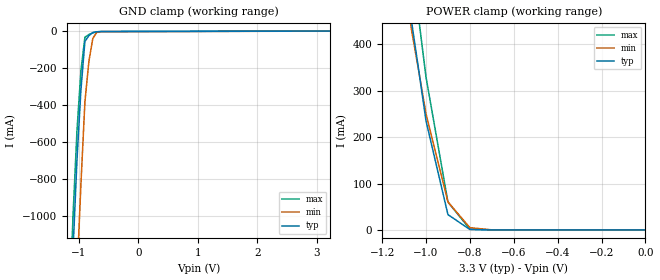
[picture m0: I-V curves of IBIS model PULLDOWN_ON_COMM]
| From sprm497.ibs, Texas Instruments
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|   Model Cell PULLDOWN_ON_COMM
[Model]   PULLDOWN_ON_COMM
Model_type   Input
Polarity   Non-Inverting
Vinl =  0.8
Vinh =  2
C_comp   0.8695239p   0.8563616p   0.8781626p
[Model Spec]
Vinl   0.8   0.8   0.8
Vinh   2   2   2
[Temperature Range]   25   105   0
[Voltage Range]   3.3   3.14   3.47
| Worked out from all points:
|   GND clamp passes 1 mA (typ) near -0.58 V on its own axis
|   POWER clamp passes 1 mA (typ) near -0.79 V on its own axis
[POWER_clamp]
|   voltage   I(typ)   I(min)   I(max)
-3.3V     9.572A     8.242A     10.54A
-1.067V   452.2mA    433.2mA    579.4mA
-1.033V   343.5mA    341.7mA    454.3mA
-1V       234.9mA    250.1mA    329.2mA
-900mV    33.1mA     60.41mA    60.11mA
-800mV    1.106mA    4.959mA    1.777mA
-700mV    117.1uA    319.8uA    148.3uA
-11.55fV  93.69uA    61.44uA    121.1uA
[GND_clamp]
|   voltage   I(typ)   I(min)   I(max)
-3.3V     -22.43A    -23.04A    -22.26A
-1.167V   -1.763A    -2.446A    -1.569A
-1.1V     -1.191A    -1.863A    -1.003A
-1.033V   -696.7mA   -1.322A    -538.1mA
-966.7mV  -318.5mA   -829.3mA   -215.1mA
-900mV    -56.2mA    -384.9mA   -33.57mA
-833.3mV  -25.19mA   -165.5mA   -18.58mA
-766.7mV  -7.722mA   -39.45mA   -8.986mA
-700mV    -3.804mA   -6.766mA   -4.783mA
-633.3mV  -1.959mA   -3.363mA   -2.454mA
3.233V    93.67uA    61.45uA    121uA
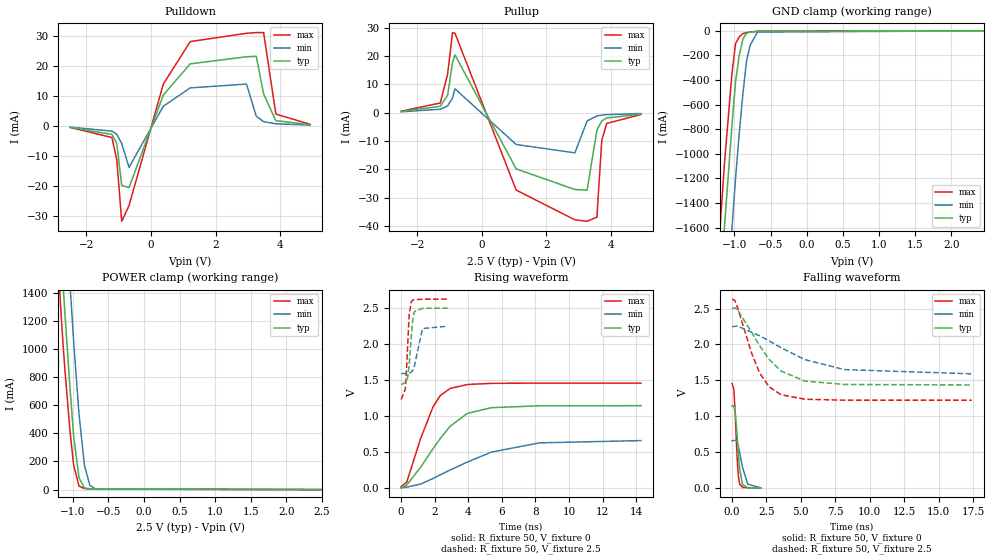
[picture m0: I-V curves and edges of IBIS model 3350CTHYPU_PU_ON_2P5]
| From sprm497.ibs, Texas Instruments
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|   Model Cell 3350CTHYPU_PU_ON_2P5
|BC3350CTHYPU_PU_ON_2P5
[Model]   3350CTHYPU_PU_ON_2P5
Model_type   I/O
Polarity   Non-Inverting
Enable   Active-Low
Vinl =  0.7V
Vinh =  1.7V
Cref =  15.0000pF
Rref =  100.0000M
Vref =  0V
Vmeas =  1.25
C_comp   1.471008p   1.454665p   1.48896p
[Model Spec]
Vinl   0.7V   0.7V   0.7V
Vinh   1.7V   1.7V   1.7V
[Temperature Range]   25   125   -40
[Voltage Range]   2.5   2.25   2.625
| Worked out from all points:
|   slope of the pulldown table from 0 to 0.375 V, typ, clamps not added: 36.8 ohm
|   slope of the pullup table from 0 to 0.375 V, typ, clamps not added: 43.3 ohm
|   GND clamp passes 1 mA (typ) near -0.57 V on its own axis
|   POWER clamp passes 1 mA (typ) near -0.52 V on its own axis
|   rising waveform, R_fixture 50, V_fixture 0: 20-80 % time 2.16ns typ, 3.86ns min, 1.36ns max; typ from 0.003 V to 1.14 V
|   rising waveform, R_fixture 50, V_fixture 2.5: 20-80 % time 215ps typ, 318ps min, 170ps max; typ from 1.44 V to 2.5 V
|   falling waveform, R_fixture 50, V_fixture 0: 20-80 % time 277ps typ, 444ps min, 210ps max; typ from 1.14 V to 0.003 V
|   falling waveform, R_fixture 50, V_fixture 2.5: 20-80 % time 2.38ns typ, 4.27ns min, 1.65ns max; typ from 2.5 V to 1.44 V
[POWER_clamp]
|   voltage   I(typ)   I(min)   I(max)
-2.5V     14.49A     15.27A     14.05A
-1.187V   1.915A     2.738A     1.465A
-1.162V   1.698A     2.516A     1.258A
-1.136V   1.481A     2.293A     1.051A
-1.111V   1.28A      2.079A     875.8mA
-1.035V   711.3mA    1.451A     408.4mA
-984.8mV  377.9mA    1.052A     173.1mA
-909.1mV  83.53mA    532.5mA    24.3mA
-833.3mV  11.48mA    171.8mA    7.346mA
-757.6mV  4.404mA    30.74mA    5.118mA
-681.8mV  2.914mA    5.106mA    3.546mA
2.5V      127.5pA    9.115nA    3.788pA
[Pulldown]
|   voltage   I(typ)   I(min)   I(max)
-2.5V     -481.1uA   -397.3uA   -508.7uA
-1.212V   -2.823mA   -1.735mA   -3.853mA
-1.061V   -5.827mA   -2.765mA   -11.27mA
-909.1mV  -19.76mA   -5.838mA   -31.7mA
-681.8mV  -20.51mA   -13.77mA   -26.47mA
378.8mV   10.27mA    6.528mA    13.88mA
1.212V    20.63mA    12.64mA    28.03mA
2.955V    22.98mA    13.91mA    30.79mA
3.258V    23.15mA    3.189mA    31.03mA
3.485V    10.6mA     1.427mA    31.01mA
3.864V    1.733mA    710uA      3.928mA
4.924V    445.6uA    287.2uA    553.5uA
[Pullup]
|   voltage   I(typ)   I(min)   I(max)
-2.5V     459.9uA    322.6uA    529.5uA
-1.288V   2.256mA    1.218mA    3.421mA
-1.061V   6.152mA    2.378mA    13.64mA
-909.1mV  17.71mA    5.195mA    28.32mA
-833.3mV  20.44mA    8.44mA     28.06mA
1.061V    -19.86mA   -11.24mA   -27.34mA
2.879V    -27.14mA   -14.19mA   -37.86mA
3.258V    -27.41mA   -2.905mA   -38.38mA
3.561V    -6.118mA   -1.138mA   -36.93mA
3.712V    -2.921mA   -859.9uA   -9.776mA
3.864V    -1.868mA   -689uA     -3.792mA
4.924V    -509.7uA   -284.1uA   -641.8uA
[GND_clamp]
|   voltage   I(typ)   I(min)   I(max)
-2.5V     -14.63A    -15.47A    -14.16A
-1.237V   -2.471A    -3.372A    -1.946A
-1.187V   -2.02A     -2.917A    -1.498A
-1.136V   -1.576A    -2.468A    -1.061A
-1.035V   -772.8mA   -1.611A    -351.9mA
-984.8mV  -415.6mA   -1.202A    -102.2mA
-934.3mV  -199.9mA   -837.3mA   -50.96mA
-883.8mV  -67.53mA   -518.4mA   -21.77mA
-833.3mV  -18.37mA   -244.8mA   -14.6mA
-782.8mV  -11.58mA   -117.1mA   -10.11mA
-681.8mV  -3.895mA   -10.62mA   -3.19mA
2.449V    -2.997uA   10.17uA    -14.14uA
[Ramp]
| variable   typ   min   max
dV/dt_f   0.646001/2.401756n   0.4024633/4.351377n   0.849555/1.649975n
dV/dt_r  0.6854441/2.159748n   0.3955803/3.87771n   0.8734082/1.364811n
R_load = 50
[Rising Waveform]
R_fixture = 50
V_fixture = 0
V_fixture_min = 0
V_fixture_max = 0
|   time   V(typ)   V(min)   V(max)
0s        3.271mV    322.8uV    17.47mV
330ps     39.17mV    11.1mV     78.38mV
1.155ns   285.3mV    52.48mV    682.5mV
1.896ns   544.2mV    130mV      1.124V
2.334ns   687.3mV    183mV      1.285V
2.922ns   856.9mV    248.1mV    1.382V
3.942ns   1.035V     359mV      1.437V
5.376ns   1.115V     497.4mV    1.453V
8.256ns   1.141V     625.9mV    1.457V
14.29ns   1.143V     657.3mV    1.457V
[Rising Waveform]
R_fixture = 50
V_fixture = 2.5
V_fixture_min = 2.25
V_fixture_max = 2.625
|   time   V(typ)   V(min)   V(max)
0s        1.436V     1.588V     1.228V
246ps     1.464V     1.591V     1.373V
303ps     1.476V     1.594V     1.555V
381ps     1.528V     1.597V     1.947V
477ps     1.706V     1.599V     2.404V
603ps     2.096V     1.608V     2.587V
690ps     2.336V     1.633V     2.61V
783ps     2.449V     1.688V     2.617V
1.272ns   2.496V     2.215V     2.622V
2.781ns   2.498V     2.248V     2.624V
[Falling Waveform]
R_fixture = 50
V_fixture = 0
V_fixture_min = 0
V_fixture_max = 0
|   time   V(typ)   V(min)   V(max)
0s        1.143V     659.7mV    1.458V
135ps     1.145V     660.3mV    1.377V
240ps     1.046V     668.3mV    1.011V
342ps     812.2mV    653.5mV    544.8mV
411ps     618.5mV    618.9mV    302.5mV
477ps     442.4mV    568.7mV    150.7mV
558ps     267.5mV    493.1mV    55.46mV
768ps     45.38mV    283.6mV    8.79mV
1.149ns   5.117mV    53.3mV     3.784mV
2.091ns   2.649mV    3.031mV    2.327mV
[Falling Waveform]
R_fixture = 50
V_fixture = 2.5
V_fixture_min = 2.25
V_fixture_max = 2.625
|   time   V(typ)   V(min)   V(max)
0s        2.499V     2.25V      2.632V
192ps     2.513V     2.251V     2.617V
384ps     2.488V     2.258V     2.527V
1.437ns   2.167V     2.169V     1.873V
2.01ns    1.981V     2.12V      1.603V
2.691ns   1.793V     2.052V     1.411V
3.564ns   1.63V      1.955V     1.3V
5.298ns   1.49V      1.789V     1.237V
8.16ns    1.443V     1.65V      1.224V
17.41ns   1.436V     1.591V     1.224V
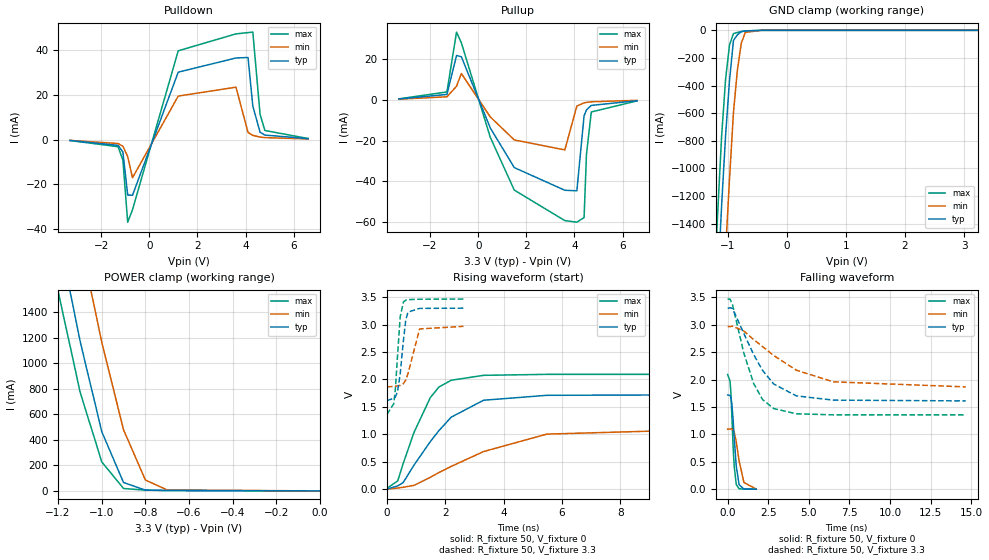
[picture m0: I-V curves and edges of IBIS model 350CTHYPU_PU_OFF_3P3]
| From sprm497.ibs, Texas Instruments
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|   Model Cell 350CTHYPU_PU_OFF_3P3
|BC3350CTHYPU_PU_OFF_3P3
[Model]   350CTHYPU_PU_OFF_3P3
Model_type   I/O
Polarity   Non-Inverting
Enable   Active-Low
Vinl =  0.8V
Vinh =  2V
Cref =  15.0000pF
Rref =  100.0000M
Vref =  0V
Vmeas =  1.65
C_comp   0.8695239p   0.8584917p   0.8767304p
[Model Spec]
Vinl   0.8V   0.8V   0.8V
Vinh   2V   2V   2V
[Temperature Range]   25   125   -40
[Voltage Range]   3.3   2.97   3.465
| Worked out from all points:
|   slope of the pulldown table from 0 to 0.495 V, typ, clamps not added: 30.2 ohm
|   slope of the pullup table from 0 to 0.495 V, typ, clamps not added: 36.2 ohm
|   GND clamp passes 1 mA (typ) near -0.57 V on its own axis
|   POWER clamp passes 1 mA (typ) near -0.52 V on its own axis
|   rising waveform, R_fixture 50, V_fixture 0: 20-80 % time 1.52ns typ, 2.8ns min, 962ps max; typ from 0.001 V to 1.72 V
|   rising waveform, R_fixture 50, V_fixture 3.3: 20-80 % time 193ps typ, 278ps min, 155ps max; typ from 1.61 V to 3.3 V
|   falling waveform, R_fixture 50, V_fixture 0: 20-80 % time 242ps typ, 371ps min, 190ps max; typ from 1.72 V to 0.002 V
|   falling waveform, R_fixture 50, V_fixture 3.3: 20-80 % time 1.92ns typ, 3.35ns min, 1.32ns max; typ from 3.3 V to 1.61 V
[POWER_clamp]
|   voltage   I(typ)   I(min)   I(max)
-3.3V     22.37A     23.12A     21.96A
-1.2V     2.026A     2.853A     1.569A
-1.167V   1.745A     2.562A     1.307A
-1.133V   1.464A     2.272A     1.044A
-1.1V     1.183A     1.981A     781.9mA
-1.067V   943.8mA    1.709A     597.2mA
-1.033V   704.5mA    1.438A     412.6mA
-1V       465.3mA    1.167A     228mA
-900mV    65.78mA    478.8mA    18.98mA
-800mV    6.477mA    85.44mA    6.096mA
-700mV    3.152mA    7.568mA    3.834mA
0V        276.4pA    13.39nA    14.63pA
[Pulldown]
|   voltage   I(typ)   I(min)   I(max)
-3.3V     -379.4uA   -330.9uA   -386.9uA
-1.3V     -2.568mA   -1.749mA   -3.18mA
-1.1V     -5.533mA   -2.961mA   -9.161mA
-900mV    -24.8mA    -7.62mA    -36.98mA
-700mV    -24.92mA   -17.08mA   -31.4mA
1.2V      30.22mA    19.51mA    39.79mA
3.6V      36.57mA    23.5mA     47.37mA
4.1V      36.79mA    3.231mA    47.94mA
4.3V      15.06mA    1.903mA    48.17mA
4.6V      3.307mA    1.155mA    11.41mA
4.8V      2.043mA    911.4uA    4.087mA
6.6V      436uA      308.8uA    502.3uA
[Pullup]
|   voltage   I(typ)   I(min)   I(max)
-3.3V     352.6uA    257.6uA    391.7uA
-1.3V     2.559mA    1.411mA    3.79mA
-900mV    21.62mA    6.557mA    33.08mA
-700mV    21.01mA    12.8mA     27.85mA
500mV     -13.79mA   -8.403mA   -18.35mA
1.5V      -33.25mA   -19.7mA    -44.26mA
3.6V      -44.33mA   -24.58mA   -59.17mA
4.1V      -44.61mA   -3.141mA   -59.96mA
4.4V      -7.897mA   -1.57mA    -57.69mA
4.5V      -4.997mA   -1.34mA    -26.74mA
4.7V      -2.803mA   -1.033mA   -6.023mA
6.6V      -515.4uA   -319.6uA   -597.7uA
[GND_clamp]
|   voltage   I(typ)   I(min)   I(max)
-3.3V     -22.52A    -23.33A    -22.07A
-1.233V   -2.436A    -3.336A    -1.911A
-1.167V   -1.845A    -2.739A    -1.328A
-1.1V     -1.269A    -2.151A    -766.5mA
-1.033V   -763.8mA   -1.597A    -354.9mA
-966.7mV  -365.3mA   -1.079A    -107.1mA
-900mV    -73.53mA   -596.8mA   -23.28mA
-833.3mV  -32.6mA    -287.4mA   -15.31mA
-766.7mV  -9.653mA   -93.48mA   -8.887mA
-700mV    -4.682mA   -15.11mA   -4.019mA
-433.3mV  -68.38uA   -267.7uA   -20.98uA
3.233V    -607.7pA   11.46uA    -20.01pA
[Ramp]
| variable   typ   min   max
dV/dt_f   1.022935/1.925801n   0.6709236/3.394756n   1.276307/1.318375n
dV/dt_r   1.031671/1.518274n   0.6578416/2.810928n   1.25571/0.9654319n
R_load = 50
[Rising Waveform]
R_fixture = 50
V_fixture = 0
V_fixture_min = 0
V_fixture_max = 0
|   time   V(typ)   V(min)   V(max)
0s        1.193mV    -365.2uV   12.74mV
372ps     59.48mV    20.32mV    150.8mV
558ps     119.4mV    34.7mV     464.8mV
930ps     438mV      68.78mV    1.035V
1.488ns   867.2mV    216.3mV    1.668V
1.782ns   1.066V     301.8mV    1.861V
2.202ns   1.311V     413.9mV    1.984V
3.309ns   1.62V      684.4mV    2.074V
5.478ns   1.71V      1.003V     2.092V
11.41ns   1.719V     1.093V     2.092V
[Rising Waveform]
R_fixture = 50
V_fixture = 3.3
V_fixture_min = 2.97
V_fixture_max = 3.465
|   time   V(typ)   V(min)   V(max)
0s        1.612V     1.865V     1.362V
237ps     1.657V     1.87V      1.557V
291ps     1.68V      1.875V     1.819V
366ps     1.777V     1.883V     2.434V
456ps     2.098V     1.891V     3.14V
567ps     2.713V     1.922V     3.41V
648ps     3.084V     1.99V      3.445V
723ps     3.226V     2.105V     3.454V
1.122ns   3.294V     2.92V      3.461V
2.625ns   3.298V     2.967V     3.464V
[Falling Waveform]
R_fixture = 50
V_fixture = 0
V_fixture_min = 0
V_fixture_max = 0
|   time   V(typ)   V(min)   V(max)
0s        1.719V     1.096V     2.094V
150ps     1.713V     1.097V     1.976V
201ps     1.672V     1.101V     1.759V
252ps     1.584V     1.103V     1.408V
336ps     1.283V     1.086V     791.6mV
402ps     960.1mV    1.044V     431.4mV
531ps     424.2mV    868.6mV    86.73mV
708ps     82.31mV    516.3mV    8.178mV
1.002ns   4.914mV    123.3mV    2.274mV
1.761ns   1.549mV    2.989mV    1.096mV
[Falling Waveform]
R_fixture = 50
V_fixture = 3.3
V_fixture_min = 2.97
V_fixture_max = 3.465
|   time   V(typ)   V(min)   V(max)
0s        3.299V     2.97V      3.471V
153ps     3.313V     2.969V     3.468V
306ps     3.298V     2.976V     3.363V
993ps     2.846V     2.889V     2.49V
1.605ns   2.457V     2.731V     1.929V
2.148ns   2.17V      2.605V     1.639V
2.838ns   1.921V     2.441V     1.472V
4.23ns    1.704V     2.173V     1.377V
6.507ns   1.626V     1.96V      1.358V
14.67ns   1.612V     1.868V     1.357V
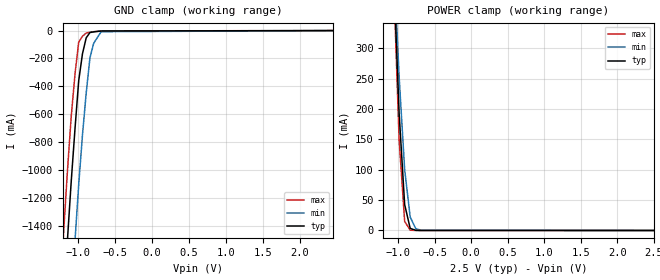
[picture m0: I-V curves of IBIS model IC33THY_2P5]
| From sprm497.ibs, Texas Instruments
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|   Model Cell IC33THY_2P5
|IC33THY_2P5
[Model]   IC33THY_2P5
Model_type   Input
Polarity   Non-Inverting
Vinl =  0.7V
Vinh =  1.7V
C_comp   0.8865095p   0.8692363p   0.9045224p
[Model Spec]
Vinl   0.7V   0.7V   0.7V
Vinh   1.7V   1.7V   1.7V
[Temperature Range]   25   125   -40
[Voltage Range]   2.5   2.25   2.625
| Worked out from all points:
|   GND clamp passes 1 mA (typ) near -0.59 V on its own axis
|   POWER clamp passes 1 mA (typ) near -0.78 V on its own axis
[POWER_clamp]
|   voltage   I(typ)   I(min)   I(max)
-2.5V     6.227A     5.3A       7.062A
-1.061V   424.9mA    451.3mA    412mA
-1.035V   347.6mA    385.3mA    324.4mA
-1.01V    270.2mA    319.2mA    236.7mA
-984.8mV  192.9mA    253.2mA    149.1mA
-909.1mV  42.62mA    100.2mA    14.97mA
-833.3mV  3.49mA     22.09mA    446.6uA
-757.6mV  205uA      3.031mA    11.51uA
-681.8mV  11.71uA    362.6uA    295.7nA
2.5V      100.3pA    7.209nA    2.975pA
[GND_clamp]
|   voltage   I(typ)   I(min)   I(max)
-2.5V     -14.54A    -15.35A    -14.09A
-1.187V   -1.936A    -2.804A    -1.434A
-1.136V   -1.495A    -2.357A    -999.4mA
-1.086V   -1.083A    -1.925A    -617.7mA
-1.035V   -704.6mA   -1.508A    -312mA
-984.8mV  -359mA     -1.104A    -82.31mA
-934.3mV  -166.9mA   -750.5mA   -40.95mA
-883.8mV  -51.98mA   -447.8mA   -17.4mA
-833.3mV  -14.26mA   -195.7mA   -11.66mA
-782.8mV  -9.084mA   -91.3mA    -8.049mA
-681.8mV  -3.07mA    -7.921mA   -2.48mA
2.449V    95.4pA     8.759nA    2.18pA
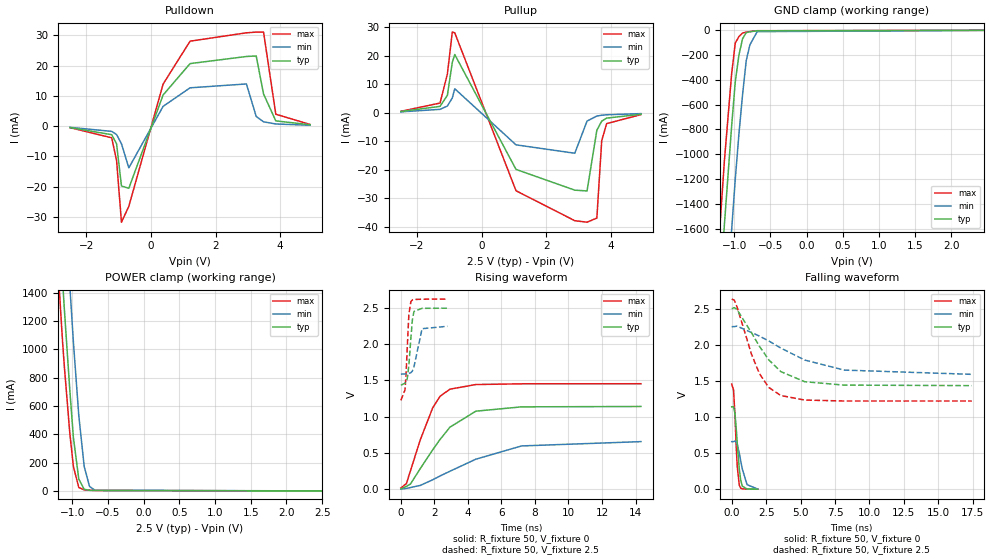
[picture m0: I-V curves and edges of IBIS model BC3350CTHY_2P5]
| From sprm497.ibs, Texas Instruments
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|   Model Cell BC3350CTHY_2P5
|BC3350CTHY_2P5
[Model]   BC3350CTHY_2P5
Model_type   I/O
Polarity   Non-Inverting
Enable   Active-Low
Vinl =  0.7V
Vinh =  1.7V
Cref =  15.0000pF
Rref =  100.0000M
Vref =  0V
Vmeas =  1.25
C_comp   1.450984p   1.434576p   1.469122p
[Model Spec]
Vinl   0.7V   0.7V   0.7V
Vinh   1.7V   1.7V   1.7V
[Temperature Range]   25   125   -40
[Voltage Range]   2.5   2.25   2.625
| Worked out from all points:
|   slope of the pulldown table from 0 to 0.375 V, typ, clamps not added: 36.8 ohm
|   slope of the pullup table from 0 to 0.375 V, typ, clamps not added: 43.3 ohm
|   GND clamp passes 1 mA (typ) near -0.58 V on its own axis
|   POWER clamp passes 1 mA (typ) near -0.52 V on its own axis
|   rising waveform, R_fixture 50, V_fixture 0: 20-80 % time 2.16ns typ, 3.86ns min, 1.36ns max; typ from 0.002 V to 1.14 V
|   rising waveform, R_fixture 50, V_fixture 2.5: 20-80 % time 213ps typ, 316ps min, 168ps max; typ from 1.43 V to 2.5 V
|   falling waveform, R_fixture 50, V_fixture 0: 20-80 % time 276ps typ, 443ps min, 209ps max; typ from 1.14 V to 0.001 V
|   falling waveform, R_fixture 50, V_fixture 2.5: 20-80 % time 2.38ns typ, 4.28ns min, 1.65ns max; typ from 2.5 V to 1.43 V
[POWER_clamp]
|   voltage   I(typ)   I(min)   I(max)
-2.5V     14.49A     15.27A     14.05A
-1.187V   1.915A     2.738A     1.465A
-1.162V   1.698A     2.516A     1.258A
-1.136V   1.481A     2.293A     1.051A
-1.111V   1.28A      2.079A     875.8mA
-1.035V   711.3mA    1.451A     408.3mA
-984.8mV  377.8mA    1.051A     173mA
-909.1mV  83.47mA    532.5mA    24.21mA
-833.3mV  11.42mA    171.8mA    7.264mA
-757.6mV  4.351mA    30.7mA     5.044mA
-681.8mV  2.867mA    5.071mA    3.48mA
2.5V      127.5pA    9.115nA    3.788pA
[Pulldown]
|   voltage   I(typ)   I(min)   I(max)
-2.5V     -481.1uA   -397.3uA   -508.7uA
-1.212V   -2.823mA   -1.735mA   -3.852mA
-1.061V   -5.827mA   -2.764mA   -11.27mA
-909.1mV  -19.76mA   -5.837mA   -31.7mA
-681.8mV  -20.51mA   -13.77mA   -26.47mA
378.8mV   10.27mA    6.528mA    13.88mA
1.212V    20.63mA    12.64mA    28.03mA
2.955V    22.98mA    13.92mA    30.79mA
3.258V    23.15mA    3.189mA    31.03mA
3.485V    10.6mA     1.427mA    31.01mA
3.864V    1.733mA    710uA      3.927mA
4.924V    445.6uA    287.2uA    553.5uA
[Pullup]
|   voltage   I(typ)   I(min)   I(max)
-2.5V     459.9uA    322.6uA    529.4uA
-1.288V   2.256mA    1.218mA    3.421mA
-1.061V   6.151mA    2.378mA    13.64mA
-909.1mV  17.71mA    5.194mA    28.32mA
-833.3mV  20.44mA    8.44mA     28.06mA
1.061V    -19.86mA   -11.24mA   -27.34mA
2.879V    -27.14mA   -14.19mA   -37.86mA
3.258V    -27.41mA   -2.905mA   -38.38mA
3.561V    -6.117mA   -1.138mA   -36.93mA
3.712V    -2.921mA   -859.9uA   -9.775mA
3.864V    -1.868mA   -689uA     -3.792mA
4.924V    -509.7uA   -284.1uA   -641.8uA
[GND_clamp]
|   voltage   I(typ)   I(min)   I(max)
-2.5V     -14.63A    -15.47A    -14.16A
-1.237V   -2.471A    -3.372A    -1.946A
-1.187V   -2.02A     -2.917A    -1.498A
-1.136V   -1.576A    -2.468A    -1.061A
-1.035V   -772.8mA   -1.611A    -351.9mA
-984.8mV  -415.6mA   -1.202A    -102.1mA
-934.3mV  -199.9mA   -837.3mA   -50.88mA
-883.8mV  -67.47mA   -518.4mA   -21.68mA
-833.3mV  -18.31mA   -244.8mA   -14.52mA
-782.8mV  -11.52mA   -117mA     -10.03mA
-681.8mV  -3.837mA   -10.58mA   -3.106mA
2.449V    -729.5pA   2.278uA    -25.62pA
[Ramp]
| variable   typ   min   max
dV/dt_f  0.6473411/2.403913n   0.4030757/4.35657n   0.8515155/1.651691n
dV/dt_r  0.6849557/2.161819n   0.3951677/3.879292n   0.87298/1.365572n
R_load = 50
[Rising Waveform]
R_fixture = 50
V_fixture = 0
V_fixture_min = 0
V_fixture_max = 0
|   time   V(typ)   V(min)   V(max)
0s        2.152mV    -451.5uV   16.14mV
330ps     37.98mV    10.32mV    76.45mV
576ps     71.62mV    22.1mV     254.9mV
1.155ns   282.5mV    51.27mV    678.8mV
1.899ns   542.3mV    128.7mV    1.122V
2.337ns   685.3mV    181.7mV    1.282V
2.928ns   855.5mV    247mV      1.38V
4.47ns    1.076V     413.1mV    1.444V
7.2ns     1.136V     596.4mV    1.454V
14.32ns   1.141V     655.9mV    1.455V
[Rising Waveform]
R_fixture = 50
V_fixture = 2.5
V_fixture_min = 2.25
V_fixture_max = 2.625
|   time   V(typ)   V(min)   V(max)
0s        1.434V     1.588V     1.225V
246ps     1.462V     1.59V      1.371V
303ps     1.474V     1.593V     1.555V
381ps     1.526V     1.596V     1.951V
477ps     1.706V     1.598V     2.412V
600ps     2.092V     1.607V     2.59V
687ps     2.335V     1.631V     2.613V
780ps     2.452V     1.686V     2.618V
1.266ns   2.496V     2.215V     2.622V
2.772ns   2.498V     2.248V     2.624V
[Falling Waveform]
R_fixture = 50
V_fixture = 0
V_fixture_min = 0
V_fixture_max = 0
|   time   V(typ)   V(min)   V(max)
0s        1.141V     658.3mV    1.456V
135ps     1.143V     658.8mV    1.374V
237ps     1.048V     666.8mV    1.018V
339ps     815.7mV    653.1mV    549.7mV
408ps     622mV      619.1mV    304.8mV
549ps     280mV      499.8mV    57.43mV
651ps     129mV      396.4mV    15.61mV
765ps     43.4mV     284.2mV    5.525mV
1.113ns   3.151mV    63.44mV    1.715mV
1.887ns   1.202mV    2.26mV     889.6uV
[Falling Waveform]
R_fixture = 50
V_fixture = 2.5
V_fixture_min = 2.25
V_fixture_max = 2.625
|   time   V(typ)   V(min)   V(max)
0s        2.499V     2.25V      2.632V
192ps     2.513V     2.251V     2.617V
384ps     2.488V     2.258V     2.526V
1.437ns   2.166V     2.169V     1.869V
2.01ns    1.979V     2.12V      1.601V
2.691ns   1.791V     2.052V     1.409V
3.564ns   1.628V     1.954V     1.297V
5.298ns   1.488V     1.788V     1.234V
8.16ns    1.441V     1.649V     1.221V
17.42ns   1.434V     1.59V      1.221V
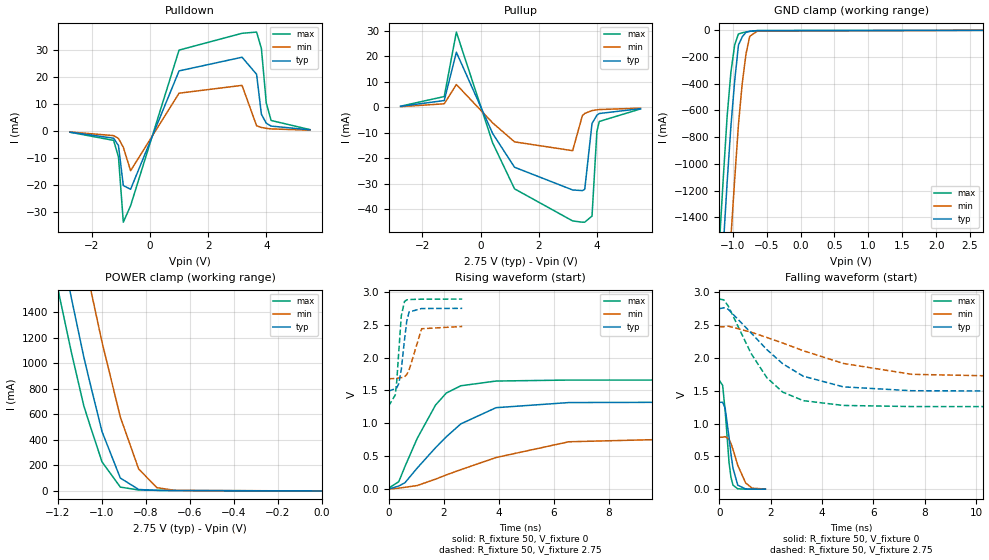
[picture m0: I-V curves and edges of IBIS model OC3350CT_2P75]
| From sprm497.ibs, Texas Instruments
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|CELL IN NORMAL MODE AT 3.3 NOM VOLTAGE
|   Model Cell OC3350CT_2P75
|OC3350CT_2P75
[Model]   OC3350CT_2P75
Model_type   3-state
Polarity   Non-Inverting
Enable   Active-Low
Cref =  15.0000pF
Rref =  100.0000M
Vref =  0V
Vmeas =  1.375
C_comp   1.334437p   1.32495p   1.341564p
[Temperature Range]   25   125   -40
[Voltage Range]   2.75   2.475   2.89
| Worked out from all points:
|   slope of the pulldown table from 0 to 0.412 V, typ, clamps not added: 34.2 ohm
|   slope of the pullup table from 0 to 0.412 V, typ, clamps not added: 40.5 ohm
|   GND clamp passes 1 mA (typ) near -0.59 V on its own axis
|   POWER clamp passes 1 mA (typ) near -0.52 V on its own axis
|   rising waveform, R_fixture 50, V_fixture 0: 20-80 % time 1.91ns typ, 3.46ns min, 1.2ns max; typ from 0.002 V to 1.32 V
|   rising waveform, R_fixture 50, V_fixture 2.75: 20-80 % time 204ps typ, 300ps min, 161ps max; typ from 1.49 V to 2.75 V
|   falling waveform, R_fixture 50, V_fixture 0: 20-80 % time 259ps typ, 412ps min, 197ps max; typ from 1.32 V to 0.001 V
|   falling waveform, R_fixture 50, V_fixture 2.75: 20-80 % time 2.21ns typ, 3.92ns min, 1.52ns max; typ from 2.75 V to 1.49 V
[POWER_clamp]
|   voltage   I(typ)   I(min)   I(max)
-2.75V    16.94A     17.72A     16.52A
-1.194V   1.981A     2.806A     1.529A
-1.139V   1.509A     2.319A     1.084A
-1.083V   1.051A     1.84A      668.4mA
-1.056V   856mA      1.616A     521.6mA
-1.028V   660.6mA    1.391A     374.7mA
-1V       465.3mA    1.167A     227.9mA
-916.7mV  101mA      578.9mA    30.07mA
-833.3mV  11.42mA    171.8mA    7.264mA
-750mV    4.141mA    25.39mA    4.875mA
-666.7mV  2.647mA    3.743mA    3.197mA
0V        159.9pA    10.11nA    5.671pA
[Pulldown]
|   voltage   I(typ)   I(min)   I(max)
-2.75V    -442uA     -372.3uA   -461.4uA
-1.25V    -2.654mA   -1.707mA   -3.463mA
-1.083V   -5.412mA   -2.742mA   -9.567mA
-916.7mV  -20.11mA   -6.001mA   -33.59mA
-666.7mV  -21.47mA   -14.63mA   -27.52mA
1V        22.12mA    13.91mA    29.78mA
3.167V    27.16mA    16.8mA     35.98mA
3.667V    20.89mA    1.926mA    36.42mA
3.833V    6.157mA    1.295mA    30.36mA
4V        2.871mA    968.4uA    10.33mA
4.167V    1.802mA    770.5uA    3.863mA
5.5V      426.6uA    287.2uA    512.6uA
[Pullup]
|   voltage   I(typ)   I(min)   I(max)
-2.75V    418.2uA    298uA      474.9uA
-1.25V    2.701mA    1.416mA    4.261mA
-833.3mV  21.66mA    8.993mA    29.57mA
416.7mV   -10.28mA   -6.093mA   -13.97mA
1.167V    -23.49mA   -13.53mA   -31.97mA
3.167V    -32.42mA   -16.99mA   -44.58mA
3.5V      -32.66mA   -3.264mA   -45.07mA
3.583V    -32.14mA   -2.367mA   -45.06mA
3.833V    -6.322mA   -1.256mA   -42.67mA
4V        -3.056mA   -947.8uA   -9.446mA
4.083V    -2.4mA     -843.2uA   -5.518mA
5.5V      -494.4uA   -288.5uA   -602.6uA
[GND_clamp]
|   voltage   I(typ)   I(min)   I(max)
-2.75V    -17.09A    -17.92A    -16.63A
-1.194V   -2.087A    -2.985A    -1.564A
-1.139V   -1.603A    -2.493A    -1.091A
-1.083V   -1.132A    -2.008A    -639.1mA
-1.028V   -718.1mA   -1.55A     -312.2mA
-972.2mV  -377.4mA   -1.115A    -108.2mA
-916.7mV  -110.4mA   -705mA     -27.01mA
-861.1mV  -48.89mA   -398mA     -18.56mA
-805.6mV  -14.58mA   -177.9mA   -11.93mA
-750mV    -7.49mA    -44.62mA   -7.122mA
-638.9mV  -2.415mA   -6.013mA   -1.764mA
2.694V    -705pA     3.817uA    -24.81pA
[Ramp]
| variable   typ   min   max
dV/dt_f  0.7640676/2.222577n   0.4843496/3.985395n   0.9886598/1.526731n
dV/dt_r  0.7939553/1.911979n   0.4756058/3.48223n   0.9950295/1.206904n
R_load = 50
[Rising Waveform]
R_fixture = 50
V_fixture = 0
V_fixture_min = 0
V_fixture_max = 0
|   time   V(typ)   V(min)   V(max)
0s        1.625mV    -420.6uV   14.81mV
369ps     47.22mV    15.32mV    114mV
591ps     97.39mV    27.5mV     343mV
1.038ns   321mV      54.84mV    772.3mV
1.704ns   630.7mV    152.1mV    1.279V
2.094ns   795.8mV    216.7mV    1.461V
2.619ns   991.9mV    295.9mV    1.571V
3.897ns   1.238V     480.3mV    1.643V
6.543ns   1.316V     720.1mV    1.658V
13.22ns   1.323V     789.7mV    1.658V
[Rising Waveform]
R_fixture = 50
V_fixture = 2.75
V_fixture_min = 2.475
V_fixture_max = 2.89
|   time   V(typ)   V(min)   V(max)
0s        1.491V     1.678V     1.263V
240ps     1.526V     1.682V     1.431V
294ps     1.541V     1.685V     1.636V
369ps     1.606V     1.69V      2.099V
459ps     1.817V     1.694V     2.634V
576ps     2.271V     1.707V     2.852V
657ps     2.554V     1.741V     2.877V
741ps     2.693V     1.809V     2.882V
1.197ns   2.745V     2.438V     2.887V
2.67ns    2.748V     2.473V     2.889V
[Falling Waveform]
R_fixture = 50
V_fixture = 0
V_fixture_min = 0
V_fixture_max = 0
|   time   V(typ)   V(min)   V(max)
0s        1.323V     792.3mV    1.659V
132ps     1.325V     792.7mV    1.581V
231ps     1.231V     800.7mV    1.19V
381ps     789.6mV    761.3mV    405.7mV
456ps     534.8mV    697.2mV    181.1mV
534ps     322mV      607.2mV    63.49mV
720ps     61.8mV     364.7mV    6.281mV
1.029ns   3.796mV    93.71mV    1.852mV
1.284ns   1.885mV    16.25mV    1.359mV
1.794ns   1.281mV    2.498mV    955.4uV
[Falling Waveform]
R_fixture = 50
V_fixture = 2.75
V_fixture_min = 2.475
V_fixture_max = 2.89
|   time   V(typ)   V(min)   V(max)
0s        2.749V     2.475V     2.896V
177ps     2.764V     2.475V     2.884V
354ps     2.739V     2.483V     2.787V
1.233ns   2.383V     2.393V     2.072V
1.851ns   2.127V     2.311V     1.699V
2.475ns   1.909V     2.226V     1.478V
3.273ns   1.721V     2.109V     1.349V
4.827ns   1.559V     1.916V     1.276V
7.494ns   1.5V       1.75V      1.259V
16.3ns    1.491V     1.681V     1.258V
